VERSION 5.7 ;
  NOWIREEXTENSIONATPIN ON ;
  DIVIDERCHAR "/" ;
  BUSBITCHARS "[]" ;
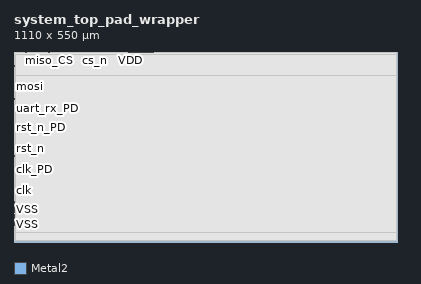
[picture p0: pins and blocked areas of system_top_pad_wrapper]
MACRO system_top_pad_wrapper
  CLASS BLOCK ;
  FOREIGN system_top_pad_wrapper ;
  ORIGIN 0.000 0.000 ;
  SIZE 1110.000 BY 550.000 ;
  PIN VDD
    DIRECTION INPUT ;
    USE POWER ;
    PORT
      LAYER Metal2 ;
        RECT 331.360 549.000 340.860 550.000 ;
    END
  END VDD
  PIN VDD
    DIRECTION INPUT ;
    USE POWER ;
    PORT
      LAYER Metal2 ;
        RECT 343.760 549.000 354.010 550.000 ;
    END
  END VDD
  PIN VDD
    DIRECTION INPUT ;
    USE POWER ;
    PORT
      LAYER Metal2 ;
        RECT 355.610 549.000 365.860 550.000 ;
    END
  END VDD
  PIN VDD
    DIRECTION INPUT ;
    USE POWER ;
    PORT
      LAYER Metal2 ;
        RECT 369.140 549.000 379.390 550.000 ;
    END
  END VDD
  PIN VDD
    DIRECTION INPUT ;
    USE POWER ;
    PORT
      LAYER Metal2 ;
        RECT 380.990 549.000 391.240 550.000 ;
    END
  END VDD
  PIN VDD
    DIRECTION INPUT ;
    USE POWER ;
    PORT
      LAYER Metal2 ;
        RECT 394.140 549.000 403.640 550.000 ;
    END
  END VDD
  PIN VSS
    DIRECTION INPUT ;
    USE GROUND ;
    PORT
      LAYER Metal2 ;
        RECT 0.000 46.360 1.000 55.860 ;
    END
  END VSS
  PIN VSS
    DIRECTION INPUT ;
    USE GROUND ;
    PORT
      LAYER Metal2 ;
        RECT 0.000 58.760 1.000 69.010 ;
    END
  END VSS
  PIN VSS
    DIRECTION INPUT ;
    USE GROUND ;
    PORT
      LAYER Metal2 ;
        RECT 0.000 70.610 1.000 80.860 ;
    END
  END VSS
  PIN VSS
    DIRECTION INPUT ;
    USE GROUND ;
    PORT
      LAYER Metal2 ;
        RECT 0.000 84.140 1.000 94.390 ;
    END
  END VSS
  PIN VSS
    DIRECTION INPUT ;
    USE GROUND ;
    PORT
      LAYER Metal2 ;
        RECT 0.000 95.990 1.000 106.240 ;
    END
  END VSS
  PIN VSS
    DIRECTION INPUT ;
    USE GROUND ;
    PORT
      LAYER Metal2 ;
        RECT 0.000 109.140 1.000 118.640 ;
    END
  END VSS
  PIN clk
    DIRECTION INPUT ;
    USE SIGNAL ;
    ANTENNAGATEAREA 4.738000 ;
    ANTENNADIFFAREA 0.410400 ;
    PORT
      LAYER Metal2 ;
        RECT 0.000 148.760 1.000 149.140 ;
    END
  END clk
  PIN clk_PD
    DIRECTION OUTPUT ;
    USE SIGNAL ;
    ANTENNADIFFAREA 0.360800 ;
    PORT
      LAYER Metal2 ;
        RECT 0.000 209.290 1.000 209.670 ;
    END
  END clk_PD
  PIN clk_PU
    DIRECTION OUTPUT ;
    USE SIGNAL ;
    ANTENNADIFFAREA 0.360800 ;
    PORT
      LAYER Metal2 ;
        RECT 0.000 213.655 1.000 214.035 ;
    END
  END clk_PU
  PIN cs_n
    DIRECTION INPUT ;
    USE SIGNAL ;
    ANTENNAGATEAREA 0.396000 ;
    ANTENNADIFFAREA 0.410400 ;
    PORT
      LAYER Metal2 ;
        RECT 233.760 549.000 234.140 550.000 ;
    END
  END cs_n
  PIN cs_n_PD
    DIRECTION OUTPUT ;
    USE SIGNAL ;
    ANTENNADIFFAREA 0.360800 ;
    PORT
      LAYER Metal2 ;
        RECT 294.290 549.000 294.670 550.000 ;
    END
  END cs_n_PD
  PIN cs_n_PU
    DIRECTION OUTPUT ;
    USE SIGNAL ;
    ANTENNADIFFAREA 0.360800 ;
    PORT
      LAYER Metal2 ;
        RECT 298.655 549.000 299.035 550.000 ;
    END
  END cs_n_PU
  PIN miso_CS
    DIRECTION OUTPUT ;
    USE SIGNAL ;
    ANTENNADIFFAREA 0.360800 ;
    PORT
      LAYER Metal2 ;
        RECT 101.260 549.000 101.640 550.000 ;
    END
  END miso_CS
  PIN miso_IE
    DIRECTION OUTPUT ;
    USE SIGNAL ;
    ANTENNADIFFAREA 0.360800 ;
    PORT
      LAYER Metal2 ;
        RECT 93.235 549.000 93.615 550.000 ;
    END
  END miso_IE
  PIN miso_IN
    DIRECTION INPUT ;
    USE SIGNAL ;
    PORT
      LAYER Metal2 ;
        RECT 33.760 549.000 34.140 550.000 ;
    END
  END miso_IN
  PIN miso_OUT
    DIRECTION OUTPUT ;
    USE SIGNAL ;
    ANTENNADIFFAREA 0.897600 ;
    PORT
      LAYER Metal2 ;
        RECT 35.220 549.000 35.600 550.000 ;
    END
  END miso_OUT
  PIN miso_PD
    DIRECTION OUTPUT ;
    USE SIGNAL ;
    ANTENNADIFFAREA 0.360800 ;
    PORT
      LAYER Metal2 ;
        RECT 94.290 549.000 94.670 550.000 ;
    END
  END miso_PD
  PIN miso_PU
    DIRECTION OUTPUT ;
    USE SIGNAL ;
    ANTENNADIFFAREA 0.360800 ;
    PORT
      LAYER Metal2 ;
        RECT 98.655 549.000 99.035 550.000 ;
    END
  END miso_PU
  PIN miso_SL
    DIRECTION OUTPUT ;
    USE SIGNAL ;
    ANTENNADIFFAREA 0.360800 ;
    PORT
      LAYER Metal2 ;
        RECT 35.950 549.000 36.330 550.000 ;
    END
  END miso_SL
  PIN miso_oe
    DIRECTION OUTPUT ;
    USE SIGNAL ;
    ANTENNADIFFAREA 0.897600 ;
    PORT
      LAYER Metal2 ;
        RECT 34.490 549.000 34.870 550.000 ;
    END
  END miso_oe
  PIN mosi
    DIRECTION INPUT ;
    USE SIGNAL ;
    ANTENNAGATEAREA 0.396000 ;
    ANTENNADIFFAREA 0.410400 ;
    PORT
      LAYER Metal2 ;
        RECT 0.000 448.760 1.000 449.140 ;
    END
  END mosi
  PIN mosi_PD
    DIRECTION OUTPUT ;
    USE SIGNAL ;
    ANTENNADIFFAREA 0.360800 ;
    PORT
      LAYER Metal2 ;
        RECT 0.000 509.290 1.000 509.670 ;
    END
  END mosi_PD
  PIN mosi_PU
    DIRECTION OUTPUT ;
    USE SIGNAL ;
    ANTENNADIFFAREA 0.360800 ;
    PORT
      LAYER Metal2 ;
        RECT 0.000 513.655 1.000 514.035 ;
    END
  END mosi_PU
  PIN rst_n
    DIRECTION INPUT ;
    USE SIGNAL ;
    ANTENNAGATEAREA 0.396000 ;
    ANTENNADIFFAREA 0.410400 ;
    PORT
      LAYER Metal2 ;
        RECT 0.000 248.760 1.000 249.140 ;
    END
  END rst_n
  PIN rst_n_PD
    DIRECTION OUTPUT ;
    USE SIGNAL ;
    ANTENNADIFFAREA 0.360800 ;
    PORT
      LAYER Metal2 ;
        RECT 0.000 309.290 1.000 309.670 ;
    END
  END rst_n_PD
  PIN rst_n_PU
    DIRECTION OUTPUT ;
    USE SIGNAL ;
    ANTENNADIFFAREA 0.360800 ;
    PORT
      LAYER Metal2 ;
        RECT 0.000 313.655 1.000 314.035 ;
    END
  END rst_n_PU
  PIN sck
    DIRECTION INPUT ;
    USE SIGNAL ;
    ANTENNAGATEAREA 0.396000 ;
    ANTENNADIFFAREA 0.410400 ;
    PORT
      LAYER Metal2 ;
        RECT 133.760 549.000 134.140 550.000 ;
    END
  END sck
  PIN sck_PD
    DIRECTION OUTPUT ;
    USE SIGNAL ;
    ANTENNADIFFAREA 0.360800 ;
    PORT
      LAYER Metal2 ;
        RECT 194.290 549.000 194.670 550.000 ;
    END
  END sck_PD
  PIN sck_PU
    DIRECTION OUTPUT ;
    USE SIGNAL ;
    ANTENNADIFFAREA 0.360800 ;
    PORT
      LAYER Metal2 ;
        RECT 198.655 549.000 199.035 550.000 ;
    END
  END sck_PU
  PIN uart_rx
    DIRECTION INPUT ;
    USE SIGNAL ;
    ANTENNAGATEAREA 0.396000 ;
    ANTENNADIFFAREA 0.410400 ;
    PORT
      LAYER Metal2 ;
        RECT 0.000 348.760 1.000 349.140 ;
    END
  END uart_rx
  PIN uart_rx_PD
    DIRECTION OUTPUT ;
    USE SIGNAL ;
    ANTENNADIFFAREA 0.360800 ;
    PORT
      LAYER Metal2 ;
        RECT 0.000 409.290 1.000 409.670 ;
    END
  END uart_rx_PD
  PIN uart_rx_PU
    DIRECTION OUTPUT ;
    USE SIGNAL ;
    ANTENNADIFFAREA 0.360800 ;
    PORT
      LAYER Metal2 ;
        RECT 0.000 413.655 1.000 414.035 ;
    END
  END uart_rx_PU
  OBS
      LAYER Nwell ;
        RECT 9.650 11.330 1100.270 537.470 ;
      LAYER Metal1 ;
        RECT 10.080 11.460 1099.840 537.340 ;
      LAYER Metal2 ;
        RECT 0.700 548.700 33.460 549.000 ;
        RECT 36.630 548.700 92.935 549.000 ;
        RECT 93.915 548.700 93.990 549.000 ;
        RECT 94.970 548.700 98.355 549.000 ;
        RECT 99.335 548.700 100.960 549.000 ;
        RECT 101.940 548.700 133.460 549.000 ;
        RECT 134.440 548.700 193.990 549.000 ;
        RECT 194.970 548.700 198.355 549.000 ;
        RECT 199.335 548.700 233.460 549.000 ;
        RECT 234.440 548.700 293.990 549.000 ;
        RECT 294.970 548.700 298.355 549.000 ;
        RECT 299.335 548.700 331.060 549.000 ;
        RECT 341.160 548.700 343.460 549.000 ;
        RECT 354.310 548.700 355.310 549.000 ;
        RECT 366.160 548.700 368.840 549.000 ;
        RECT 379.690 548.700 380.690 549.000 ;
        RECT 391.540 548.700 393.840 549.000 ;
        RECT 403.940 548.700 1106.740 549.000 ;
        RECT 0.700 514.335 1106.740 548.700 ;
        RECT 1.300 513.355 1106.740 514.335 ;
        RECT 0.700 509.970 1106.740 513.355 ;
        RECT 1.300 508.990 1106.740 509.970 ;
        RECT 0.700 449.440 1106.740 508.990 ;
        RECT 1.300 448.460 1106.740 449.440 ;
        RECT 0.700 414.335 1106.740 448.460 ;
        RECT 1.300 413.355 1106.740 414.335 ;
        RECT 0.700 409.970 1106.740 413.355 ;
        RECT 1.300 408.990 1106.740 409.970 ;
        RECT 0.700 349.440 1106.740 408.990 ;
        RECT 1.300 348.460 1106.740 349.440 ;
        RECT 0.700 314.335 1106.740 348.460 ;
        RECT 1.300 313.355 1106.740 314.335 ;
        RECT 0.700 309.970 1106.740 313.355 ;
        RECT 1.300 308.990 1106.740 309.970 ;
        RECT 0.700 249.440 1106.740 308.990 ;
        RECT 1.300 248.460 1106.740 249.440 ;
        RECT 0.700 214.335 1106.740 248.460 ;
        RECT 1.300 213.355 1106.740 214.335 ;
        RECT 0.700 209.970 1106.740 213.355 ;
        RECT 1.300 208.990 1106.740 209.970 ;
        RECT 0.700 149.440 1106.740 208.990 ;
        RECT 1.300 148.460 1106.740 149.440 ;
        RECT 0.700 118.940 1106.740 148.460 ;
        RECT 1.300 108.840 1106.740 118.940 ;
        RECT 0.700 106.540 1106.740 108.840 ;
        RECT 1.300 95.690 1106.740 106.540 ;
        RECT 0.700 94.690 1106.740 95.690 ;
        RECT 1.300 83.840 1106.740 94.690 ;
        RECT 0.700 81.160 1106.740 83.840 ;
        RECT 1.300 70.310 1106.740 81.160 ;
        RECT 0.700 69.310 1106.740 70.310 ;
        RECT 1.300 58.460 1106.740 69.310 ;
        RECT 0.700 56.160 1106.740 58.460 ;
        RECT 1.300 46.060 1106.740 56.160 ;
        RECT 0.700 4.860 1106.740 46.060 ;
      LAYER Metal3 ;
        RECT 0.650 4.860 1106.740 543.940 ;
      LAYER Metal4 ;
        RECT 3.320 4.860 1106.600 543.940 ;
      LAYER Metal5 ;
        RECT 3.180 27.610 1106.740 481.810 ;
  END
END system_top_pad_wrapper
END LIBRARY

